# Generated by FakeRAM 2.0
VERSION 5.7 ;
BUSBITCHARS "[]" ;
PROPERTYDEFINITIONS
  MACRO width INTEGER ;
  MACRO depth INTEGER ;
  MACRO banks INTEGER ;
END PROPERTYDEFINITIONS
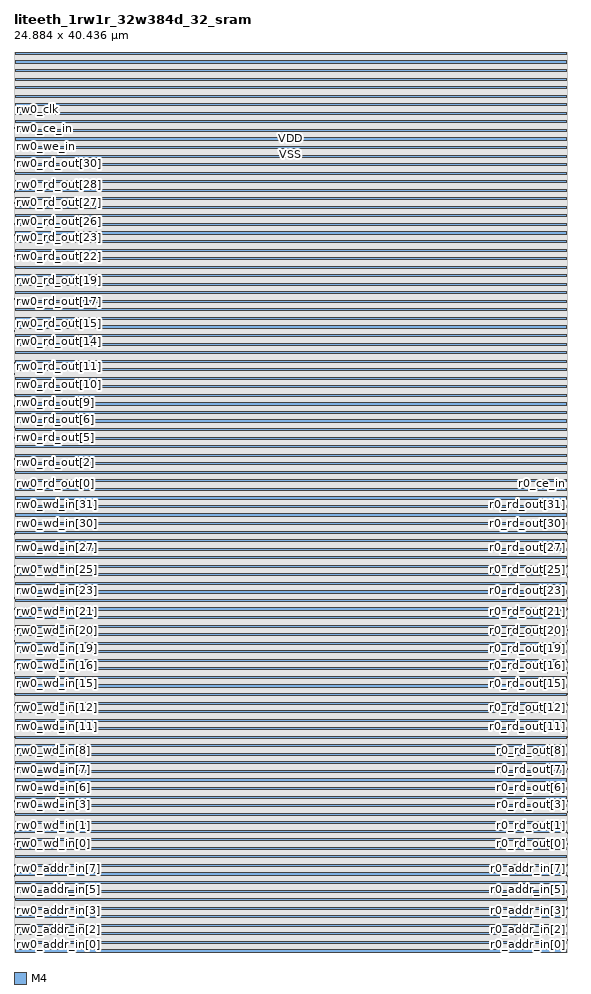
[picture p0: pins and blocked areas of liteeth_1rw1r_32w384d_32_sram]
MACRO liteeth_1rw1r_32w384d_32_sram
  PROPERTY width 32 ;
  PROPERTY depth 384 ;
  PROPERTY banks 1 ;
  FOREIGN liteeth_1rw1r_32w384d_32_sram 0 0 ;
  SYMMETRY X Y R90 ;
  SIZE 24.884 BY 40.436 ;
  CLASS BLOCK ;
  PIN r0_addr_in[0]
    DIRECTION INPUT ;
    USE SIGNAL ;
    SHAPE ABUTMENT ;
    PORT
      LAYER M4 ;
      RECT 24.860 0.048 24.884 0.072 ;
    END
  END r0_addr_in[0]
  PIN r0_addr_in[1]
    DIRECTION INPUT ;
    USE SIGNAL ;
    SHAPE ABUTMENT ;
    PORT
      LAYER M4 ;
      RECT 24.860 0.528 24.884 0.552 ;
    END
  END r0_addr_in[1]
  PIN r0_addr_in[2]
    DIRECTION INPUT ;
    USE SIGNAL ;
    SHAPE ABUTMENT ;
    PORT
      LAYER M4 ;
      RECT 24.860 1.008 24.884 1.032 ;
    END
  END r0_addr_in[2]
  PIN r0_addr_in[3]
    DIRECTION INPUT ;
    USE SIGNAL ;
    SHAPE ABUTMENT ;
    PORT
      LAYER M4 ;
      RECT 24.860 1.488 24.884 1.512 ;
    END
  END r0_addr_in[3]
  PIN r0_addr_in[4]
    DIRECTION INPUT ;
    USE SIGNAL ;
    SHAPE ABUTMENT ;
    PORT
      LAYER M4 ;
      RECT 24.860 1.968 24.884 1.992 ;
    END
  END r0_addr_in[4]
  PIN r0_addr_in[5]
    DIRECTION INPUT ;
    USE SIGNAL ;
    SHAPE ABUTMENT ;
    PORT
      LAYER M4 ;
      RECT 24.860 2.448 24.884 2.472 ;
    END
  END r0_addr_in[5]
  PIN r0_addr_in[6]
    DIRECTION INPUT ;
    USE SIGNAL ;
    SHAPE ABUTMENT ;
    PORT
      LAYER M4 ;
      RECT 24.860 2.928 24.884 2.952 ;
    END
  END r0_addr_in[6]
  PIN r0_addr_in[7]
    DIRECTION INPUT ;
    USE SIGNAL ;
    SHAPE ABUTMENT ;
    PORT
      LAYER M4 ;
      RECT 24.860 3.408 24.884 3.432 ;
    END
  END r0_addr_in[7]
  PIN r0_addr_in[8]
    DIRECTION INPUT ;
    USE SIGNAL ;
    SHAPE ABUTMENT ;
    PORT
      LAYER M4 ;
      RECT 24.860 3.888 24.884 3.912 ;
    END
  END r0_addr_in[8]
  PIN r0_rd_out[0]
    DIRECTION OUTPUT ;
    USE SIGNAL ;
    SHAPE ABUTMENT ;
    PORT
      LAYER M4 ;
      RECT 24.860 4.848 24.884 4.872 ;
    END
  END r0_rd_out[0]
  PIN r0_rd_out[1]
    DIRECTION OUTPUT ;
    USE SIGNAL ;
    SHAPE ABUTMENT ;
    PORT
      LAYER M4 ;
      RECT 24.860 5.328 24.884 5.352 ;
    END
  END r0_rd_out[1]
  PIN r0_rd_out[2]
    DIRECTION OUTPUT ;
    USE SIGNAL ;
    SHAPE ABUTMENT ;
    PORT
      LAYER M4 ;
      RECT 24.860 5.808 24.884 5.832 ;
    END
  END r0_rd_out[2]
  PIN r0_rd_out[3]
    DIRECTION OUTPUT ;
    USE SIGNAL ;
    SHAPE ABUTMENT ;
    PORT
      LAYER M4 ;
      RECT 24.860 6.288 24.884 6.312 ;
    END
  END r0_rd_out[3]
  PIN r0_rd_out[4]
    DIRECTION OUTPUT ;
    USE SIGNAL ;
    SHAPE ABUTMENT ;
    PORT
      LAYER M4 ;
      RECT 24.860 6.768 24.884 6.792 ;
    END
  END r0_rd_out[4]
  PIN r0_rd_out[5]
    DIRECTION OUTPUT ;
    USE SIGNAL ;
    SHAPE ABUTMENT ;
    PORT
      LAYER M4 ;
      RECT 24.860 7.248 24.884 7.272 ;
    END
  END r0_rd_out[5]
  PIN r0_rd_out[6]
    DIRECTION OUTPUT ;
    USE SIGNAL ;
    SHAPE ABUTMENT ;
    PORT
      LAYER M4 ;
      RECT 24.860 7.728 24.884 7.752 ;
    END
  END r0_rd_out[6]
  PIN r0_rd_out[7]
    DIRECTION OUTPUT ;
    USE SIGNAL ;
    SHAPE ABUTMENT ;
    PORT
      LAYER M4 ;
      RECT 24.860 8.208 24.884 8.232 ;
    END
  END r0_rd_out[7]
  PIN r0_rd_out[8]
    DIRECTION OUTPUT ;
    USE SIGNAL ;
    SHAPE ABUTMENT ;
    PORT
      LAYER M4 ;
      RECT 24.860 8.688 24.884 8.712 ;
    END
  END r0_rd_out[8]
  PIN r0_rd_out[9]
    DIRECTION OUTPUT ;
    USE SIGNAL ;
    SHAPE ABUTMENT ;
    PORT
      LAYER M4 ;
      RECT 24.860 9.168 24.884 9.192 ;
    END
  END r0_rd_out[9]
  PIN r0_rd_out[10]
    DIRECTION OUTPUT ;
    USE SIGNAL ;
    SHAPE ABUTMENT ;
    PORT
      LAYER M4 ;
      RECT 24.860 9.648 24.884 9.672 ;
    END
  END r0_rd_out[10]
  PIN r0_rd_out[11]
    DIRECTION OUTPUT ;
    USE SIGNAL ;
    SHAPE ABUTMENT ;
    PORT
      LAYER M4 ;
      RECT 24.860 10.128 24.884 10.152 ;
    END
  END r0_rd_out[11]
  PIN r0_rd_out[12]
    DIRECTION OUTPUT ;
    USE SIGNAL ;
    SHAPE ABUTMENT ;
    PORT
      LAYER M4 ;
      RECT 24.860 10.608 24.884 10.632 ;
    END
  END r0_rd_out[12]
  PIN r0_rd_out[13]
    DIRECTION OUTPUT ;
    USE SIGNAL ;
    SHAPE ABUTMENT ;
    PORT
      LAYER M4 ;
      RECT 24.860 11.088 24.884 11.112 ;
    END
  END r0_rd_out[13]
  PIN r0_rd_out[14]
    DIRECTION OUTPUT ;
    USE SIGNAL ;
    SHAPE ABUTMENT ;
    PORT
      LAYER M4 ;
      RECT 24.860 11.568 24.884 11.592 ;
    END
  END r0_rd_out[14]
  PIN r0_rd_out[15]
    DIRECTION OUTPUT ;
    USE SIGNAL ;
    SHAPE ABUTMENT ;
    PORT
      LAYER M4 ;
      RECT 24.860 12.048 24.884 12.072 ;
    END
  END r0_rd_out[15]
  PIN r0_rd_out[16]
    DIRECTION OUTPUT ;
    USE SIGNAL ;
    SHAPE ABUTMENT ;
    PORT
      LAYER M4 ;
      RECT 24.860 12.528 24.884 12.552 ;
    END
  END r0_rd_out[16]
  PIN r0_rd_out[17]
    DIRECTION OUTPUT ;
    USE SIGNAL ;
    SHAPE ABUTMENT ;
    PORT
      LAYER M4 ;
      RECT 24.860 13.008 24.884 13.032 ;
    END
  END r0_rd_out[17]
  PIN r0_rd_out[18]
    DIRECTION OUTPUT ;
    USE SIGNAL ;
    SHAPE ABUTMENT ;
    PORT
      LAYER M4 ;
      RECT 24.860 13.488 24.884 13.512 ;
    END
  END r0_rd_out[18]
  PIN r0_rd_out[19]
    DIRECTION OUTPUT ;
    USE SIGNAL ;
    SHAPE ABUTMENT ;
    PORT
      LAYER M4 ;
      RECT 24.860 13.968 24.884 13.992 ;
    END
  END r0_rd_out[19]
  PIN r0_rd_out[20]
    DIRECTION OUTPUT ;
    USE SIGNAL ;
    SHAPE ABUTMENT ;
    PORT
      LAYER M4 ;
      RECT 24.860 14.448 24.884 14.472 ;
    END
  END r0_rd_out[20]
  PIN r0_rd_out[21]
    DIRECTION OUTPUT ;
    USE SIGNAL ;
    SHAPE ABUTMENT ;
    PORT
      LAYER M4 ;
      RECT 24.860 14.928 24.884 14.952 ;
    END
  END r0_rd_out[21]
  PIN r0_rd_out[22]
    DIRECTION OUTPUT ;
    USE SIGNAL ;
    SHAPE ABUTMENT ;
    PORT
      LAYER M4 ;
      RECT 24.860 15.408 24.884 15.432 ;
    END
  END r0_rd_out[22]
  PIN r0_rd_out[23]
    DIRECTION OUTPUT ;
    USE SIGNAL ;
    SHAPE ABUTMENT ;
    PORT
      LAYER M4 ;
      RECT 24.860 15.888 24.884 15.912 ;
    END
  END r0_rd_out[23]
  PIN r0_rd_out[24]
    DIRECTION OUTPUT ;
    USE SIGNAL ;
    SHAPE ABUTMENT ;
    PORT
      LAYER M4 ;
      RECT 24.860 16.368 24.884 16.392 ;
    END
  END r0_rd_out[24]
  PIN r0_rd_out[25]
    DIRECTION OUTPUT ;
    USE SIGNAL ;
    SHAPE ABUTMENT ;
    PORT
      LAYER M4 ;
      RECT 24.860 16.848 24.884 16.872 ;
    END
  END r0_rd_out[25]
  PIN r0_rd_out[26]
    DIRECTION OUTPUT ;
    USE SIGNAL ;
    SHAPE ABUTMENT ;
    PORT
      LAYER M4 ;
      RECT 24.860 17.328 24.884 17.352 ;
    END
  END r0_rd_out[26]
  PIN r0_rd_out[27]
    DIRECTION OUTPUT ;
    USE SIGNAL ;
    SHAPE ABUTMENT ;
    PORT
      LAYER M4 ;
      RECT 24.860 17.808 24.884 17.832 ;
    END
  END r0_rd_out[27]
  PIN r0_rd_out[28]
    DIRECTION OUTPUT ;
    USE SIGNAL ;
    SHAPE ABUTMENT ;
    PORT
      LAYER M4 ;
      RECT 24.860 18.288 24.884 18.312 ;
    END
  END r0_rd_out[28]
  PIN r0_rd_out[29]
    DIRECTION OUTPUT ;
    USE SIGNAL ;
    SHAPE ABUTMENT ;
    PORT
      LAYER M4 ;
      RECT 24.860 18.768 24.884 18.792 ;
    END
  END r0_rd_out[29]
  PIN r0_rd_out[30]
    DIRECTION OUTPUT ;
    USE SIGNAL ;
    SHAPE ABUTMENT ;
    PORT
      LAYER M4 ;
      RECT 24.860 19.248 24.884 19.272 ;
    END
  END r0_rd_out[30]
  PIN r0_rd_out[31]
    DIRECTION OUTPUT ;
    USE SIGNAL ;
    SHAPE ABUTMENT ;
    PORT
      LAYER M4 ;
      RECT 24.860 19.728 24.884 19.752 ;
    END
  END r0_rd_out[31]
  PIN r0_ce_in
    DIRECTION INPUT ;
    USE SIGNAL ;
    SHAPE ABUTMENT ;
    PORT
      LAYER M4 ;
      RECT 24.860 20.688 24.884 20.712 ;
    END
  END r0_ce_in
  PIN r0_clk
    DIRECTION INPUT ;
    USE SIGNAL ;
    SHAPE ABUTMENT ;
    PORT
      LAYER M4 ;
      RECT 24.860 21.168 24.884 21.192 ;
    END
  END r0_clk
  PIN rw0_addr_in[0]
    DIRECTION INPUT ;
    USE SIGNAL ;
    SHAPE ABUTMENT ;
    PORT
      LAYER M4 ;
      RECT 0.000 0.048 0.024 0.072 ;
    END
  END rw0_addr_in[0]
  PIN rw0_addr_in[1]
    DIRECTION INPUT ;
    USE SIGNAL ;
    SHAPE ABUTMENT ;
    PORT
      LAYER M4 ;
      RECT 0.000 0.528 0.024 0.552 ;
    END
  END rw0_addr_in[1]
  PIN rw0_addr_in[2]
    DIRECTION INPUT ;
    USE SIGNAL ;
    SHAPE ABUTMENT ;
    PORT
      LAYER M4 ;
      RECT 0.000 1.008 0.024 1.032 ;
    END
  END rw0_addr_in[2]
  PIN rw0_addr_in[3]
    DIRECTION INPUT ;
    USE SIGNAL ;
    SHAPE ABUTMENT ;
    PORT
      LAYER M4 ;
      RECT 0.000 1.488 0.024 1.512 ;
    END
  END rw0_addr_in[3]
  PIN rw0_addr_in[4]
    DIRECTION INPUT ;
    USE SIGNAL ;
    SHAPE ABUTMENT ;
    PORT
      LAYER M4 ;
      RECT 0.000 1.968 0.024 1.992 ;
    END
  END rw0_addr_in[4]
  PIN rw0_addr_in[5]
    DIRECTION INPUT ;
    USE SIGNAL ;
    SHAPE ABUTMENT ;
    PORT
      LAYER M4 ;
      RECT 0.000 2.448 0.024 2.472 ;
    END
  END rw0_addr_in[5]
  PIN rw0_addr_in[6]
    DIRECTION INPUT ;
    USE SIGNAL ;
    SHAPE ABUTMENT ;
    PORT
      LAYER M4 ;
      RECT 0.000 2.928 0.024 2.952 ;
    END
  END rw0_addr_in[6]
  PIN rw0_addr_in[7]
    DIRECTION INPUT ;
    USE SIGNAL ;
    SHAPE ABUTMENT ;
    PORT
      LAYER M4 ;
      RECT 0.000 3.408 0.024 3.432 ;
    END
  END rw0_addr_in[7]
  PIN rw0_addr_in[8]
    DIRECTION INPUT ;
    USE SIGNAL ;
    SHAPE ABUTMENT ;
    PORT
      LAYER M4 ;
      RECT 0.000 3.888 0.024 3.912 ;
    END
  END rw0_addr_in[8]
  PIN rw0_wd_in[0]
    DIRECTION INPUT ;
    USE SIGNAL ;
    SHAPE ABUTMENT ;
    PORT
      LAYER M4 ;
      RECT 0.000 4.848 0.024 4.872 ;
    END
  END rw0_wd_in[0]
  PIN rw0_wd_in[1]
    DIRECTION INPUT ;
    USE SIGNAL ;
    SHAPE ABUTMENT ;
    PORT
      LAYER M4 ;
      RECT 0.000 5.328 0.024 5.352 ;
    END
  END rw0_wd_in[1]
  PIN rw0_wd_in[2]
    DIRECTION INPUT ;
    USE SIGNAL ;
    SHAPE ABUTMENT ;
    PORT
      LAYER M4 ;
      RECT 0.000 5.808 0.024 5.832 ;
    END
  END rw0_wd_in[2]
  PIN rw0_wd_in[3]
    DIRECTION INPUT ;
    USE SIGNAL ;
    SHAPE ABUTMENT ;
    PORT
      LAYER M4 ;
      RECT 0.000 6.288 0.024 6.312 ;
    END
  END rw0_wd_in[3]
  PIN rw0_wd_in[4]
    DIRECTION INPUT ;
    USE SIGNAL ;
    SHAPE ABUTMENT ;
    PORT
      LAYER M4 ;
      RECT 0.000 6.768 0.024 6.792 ;
    END
  END rw0_wd_in[4]
  PIN rw0_wd_in[5]
    DIRECTION INPUT ;
    USE SIGNAL ;
    SHAPE ABUTMENT ;
    PORT
      LAYER M4 ;
      RECT 0.000 7.248 0.024 7.272 ;
    END
  END rw0_wd_in[5]
  PIN rw0_wd_in[6]
    DIRECTION INPUT ;
    USE SIGNAL ;
    SHAPE ABUTMENT ;
    PORT
      LAYER M4 ;
      RECT 0.000 7.728 0.024 7.752 ;
    END
  END rw0_wd_in[6]
  PIN rw0_wd_in[7]
    DIRECTION INPUT ;
    USE SIGNAL ;
    SHAPE ABUTMENT ;
    PORT
      LAYER M4 ;
      RECT 0.000 8.208 0.024 8.232 ;
    END
  END rw0_wd_in[7]
  PIN rw0_wd_in[8]
    DIRECTION INPUT ;
    USE SIGNAL ;
    SHAPE ABUTMENT ;
    PORT
      LAYER M4 ;
      RECT 0.000 8.688 0.024 8.712 ;
    END
  END rw0_wd_in[8]
  PIN rw0_wd_in[9]
    DIRECTION INPUT ;
    USE SIGNAL ;
    SHAPE ABUTMENT ;
    PORT
      LAYER M4 ;
      RECT 0.000 9.168 0.024 9.192 ;
    END
  END rw0_wd_in[9]
  PIN rw0_wd_in[10]
    DIRECTION INPUT ;
    USE SIGNAL ;
    SHAPE ABUTMENT ;
    PORT
      LAYER M4 ;
      RECT 0.000 9.648 0.024 9.672 ;
    END
  END rw0_wd_in[10]
  PIN rw0_wd_in[11]
    DIRECTION INPUT ;
    USE SIGNAL ;
    SHAPE ABUTMENT ;
    PORT
      LAYER M4 ;
      RECT 0.000 10.128 0.024 10.152 ;
    END
  END rw0_wd_in[11]
  PIN rw0_wd_in[12]
    DIRECTION INPUT ;
    USE SIGNAL ;
    SHAPE ABUTMENT ;
    PORT
      LAYER M4 ;
      RECT 0.000 10.608 0.024 10.632 ;
    END
  END rw0_wd_in[12]
  PIN rw0_wd_in[13]
    DIRECTION INPUT ;
    USE SIGNAL ;
    SHAPE ABUTMENT ;
    PORT
      LAYER M4 ;
      RECT 0.000 11.088 0.024 11.112 ;
    END
  END rw0_wd_in[13]
  PIN rw0_wd_in[14]
    DIRECTION INPUT ;
    USE SIGNAL ;
    SHAPE ABUTMENT ;
    PORT
      LAYER M4 ;
      RECT 0.000 11.568 0.024 11.592 ;
    END
  END rw0_wd_in[14]
  PIN rw0_wd_in[15]
    DIRECTION INPUT ;
    USE SIGNAL ;
    SHAPE ABUTMENT ;
    PORT
      LAYER M4 ;
      RECT 0.000 12.048 0.024 12.072 ;
    END
  END rw0_wd_in[15]
  PIN rw0_wd_in[16]
    DIRECTION INPUT ;
    USE SIGNAL ;
    SHAPE ABUTMENT ;
    PORT
      LAYER M4 ;
      RECT 0.000 12.528 0.024 12.552 ;
    END
  END rw0_wd_in[16]
  PIN rw0_wd_in[17]
    DIRECTION INPUT ;
    USE SIGNAL ;
    SHAPE ABUTMENT ;
    PORT
      LAYER M4 ;
      RECT 0.000 13.008 0.024 13.032 ;
    END
  END rw0_wd_in[17]
  PIN rw0_wd_in[18]
    DIRECTION INPUT ;
    USE SIGNAL ;
    SHAPE ABUTMENT ;
    PORT
      LAYER M4 ;
      RECT 0.000 13.488 0.024 13.512 ;
    END
  END rw0_wd_in[18]
  PIN rw0_wd_in[19]
    DIRECTION INPUT ;
    USE SIGNAL ;
    SHAPE ABUTMENT ;
    PORT
      LAYER M4 ;
      RECT 0.000 13.968 0.024 13.992 ;
    END
  END rw0_wd_in[19]
  PIN rw0_wd_in[20]
    DIRECTION INPUT ;
    USE SIGNAL ;
    SHAPE ABUTMENT ;
    PORT
      LAYER M4 ;
      RECT 0.000 14.448 0.024 14.472 ;
    END
  END rw0_wd_in[20]
  PIN rw0_wd_in[21]
    DIRECTION INPUT ;
    USE SIGNAL ;
    SHAPE ABUTMENT ;
    PORT
      LAYER M4 ;
      RECT 0.000 14.928 0.024 14.952 ;
    END
  END rw0_wd_in[21]
  PIN rw0_wd_in[22]
    DIRECTION INPUT ;
    USE SIGNAL ;
    SHAPE ABUTMENT ;
    PORT
      LAYER M4 ;
      RECT 0.000 15.408 0.024 15.432 ;
    END
  END rw0_wd_in[22]
  PIN rw0_wd_in[23]
    DIRECTION INPUT ;
    USE SIGNAL ;
    SHAPE ABUTMENT ;
    PORT
      LAYER M4 ;
      RECT 0.000 15.888 0.024 15.912 ;
    END
  END rw0_wd_in[23]
  PIN rw0_wd_in[24]
    DIRECTION INPUT ;
    USE SIGNAL ;
    SHAPE ABUTMENT ;
    PORT
      LAYER M4 ;
      RECT 0.000 16.368 0.024 16.392 ;
    END
  END rw0_wd_in[24]
  PIN rw0_wd_in[25]
    DIRECTION INPUT ;
    USE SIGNAL ;
    SHAPE ABUTMENT ;
    PORT
      LAYER M4 ;
      RECT 0.000 16.848 0.024 16.872 ;
    END
  END rw0_wd_in[25]
  PIN rw0_wd_in[26]
    DIRECTION INPUT ;
    USE SIGNAL ;
    SHAPE ABUTMENT ;
    PORT
      LAYER M4 ;
      RECT 0.000 17.328 0.024 17.352 ;
    END
  END rw0_wd_in[26]
  PIN rw0_wd_in[27]
    DIRECTION INPUT ;
    USE SIGNAL ;
    SHAPE ABUTMENT ;
    PORT
      LAYER M4 ;
      RECT 0.000 17.808 0.024 17.832 ;
    END
  END rw0_wd_in[27]
  PIN rw0_wd_in[28]
    DIRECTION INPUT ;
    USE SIGNAL ;
    SHAPE ABUTMENT ;
    PORT
      LAYER M4 ;
      RECT 0.000 18.288 0.024 18.312 ;
    END
  END rw0_wd_in[28]
  PIN rw0_wd_in[29]
    DIRECTION INPUT ;
    USE SIGNAL ;
    SHAPE ABUTMENT ;
    PORT
      LAYER M4 ;
      RECT 0.000 18.768 0.024 18.792 ;
    END
  END rw0_wd_in[29]
  PIN rw0_wd_in[30]
    DIRECTION INPUT ;
    USE SIGNAL ;
    SHAPE ABUTMENT ;
    PORT
      LAYER M4 ;
      RECT 0.000 19.248 0.024 19.272 ;
    END
  END rw0_wd_in[30]
  PIN rw0_wd_in[31]
    DIRECTION INPUT ;
    USE SIGNAL ;
    SHAPE ABUTMENT ;
    PORT
      LAYER M4 ;
      RECT 0.000 19.728 0.024 19.752 ;
    END
  END rw0_wd_in[31]
  PIN rw0_rd_out[0]
    DIRECTION OUTPUT ;
    USE SIGNAL ;
    SHAPE ABUTMENT ;
    PORT
      LAYER M4 ;
      RECT 0.000 20.688 0.024 20.712 ;
    END
  END rw0_rd_out[0]
  PIN rw0_rd_out[1]
    DIRECTION OUTPUT ;
    USE SIGNAL ;
    SHAPE ABUTMENT ;
    PORT
      LAYER M4 ;
      RECT 0.000 21.168 0.024 21.192 ;
    END
  END rw0_rd_out[1]
  PIN rw0_rd_out[2]
    DIRECTION OUTPUT ;
    USE SIGNAL ;
    SHAPE ABUTMENT ;
    PORT
      LAYER M4 ;
      RECT 0.000 21.648 0.024 21.672 ;
    END
  END rw0_rd_out[2]
  PIN rw0_rd_out[3]
    DIRECTION OUTPUT ;
    USE SIGNAL ;
    SHAPE ABUTMENT ;
    PORT
      LAYER M4 ;
      RECT 0.000 22.128 0.024 22.152 ;
    END
  END rw0_rd_out[3]
  PIN rw0_rd_out[4]
    DIRECTION OUTPUT ;
    USE SIGNAL ;
    SHAPE ABUTMENT ;
    PORT
      LAYER M4 ;
      RECT 0.000 22.608 0.024 22.632 ;
    END
  END rw0_rd_out[4]
  PIN rw0_rd_out[5]
    DIRECTION OUTPUT ;
    USE SIGNAL ;
    SHAPE ABUTMENT ;
    PORT
      LAYER M4 ;
      RECT 0.000 23.088 0.024 23.112 ;
    END
  END rw0_rd_out[5]
  PIN rw0_rd_out[6]
    DIRECTION OUTPUT ;
    USE SIGNAL ;
    SHAPE ABUTMENT ;
    PORT
      LAYER M4 ;
      RECT 0.000 23.568 0.024 23.592 ;
    END
  END rw0_rd_out[6]
  PIN rw0_rd_out[7]
    DIRECTION OUTPUT ;
    USE SIGNAL ;
    SHAPE ABUTMENT ;
    PORT
      LAYER M4 ;
      RECT 0.000 24.048 0.024 24.072 ;
    END
  END rw0_rd_out[7]
  PIN rw0_rd_out[8]
    DIRECTION OUTPUT ;
    USE SIGNAL ;
    SHAPE ABUTMENT ;
    PORT
      LAYER M4 ;
      RECT 0.000 24.528 0.024 24.552 ;
    END
  END rw0_rd_out[8]
  PIN rw0_rd_out[9]
    DIRECTION OUTPUT ;
    USE SIGNAL ;
    SHAPE ABUTMENT ;
    PORT
      LAYER M4 ;
      RECT 0.000 25.008 0.024 25.032 ;
    END
  END rw0_rd_out[9]
  PIN rw0_rd_out[10]
    DIRECTION OUTPUT ;
    USE SIGNAL ;
    SHAPE ABUTMENT ;
    PORT
      LAYER M4 ;
      RECT 0.000 25.488 0.024 25.512 ;
    END
  END rw0_rd_out[10]
  PIN rw0_rd_out[11]
    DIRECTION OUTPUT ;
    USE SIGNAL ;
    SHAPE ABUTMENT ;
    PORT
      LAYER M4 ;
      RECT 0.000 25.968 0.024 25.992 ;
    END
  END rw0_rd_out[11]
  PIN rw0_rd_out[12]
    DIRECTION OUTPUT ;
    USE SIGNAL ;
    SHAPE ABUTMENT ;
    PORT
      LAYER M4 ;
      RECT 0.000 26.448 0.024 26.472 ;
    END
  END rw0_rd_out[12]
  PIN rw0_rd_out[13]
    DIRECTION OUTPUT ;
    USE SIGNAL ;
    SHAPE ABUTMENT ;
    PORT
      LAYER M4 ;
      RECT 0.000 26.928 0.024 26.952 ;
    END
  END rw0_rd_out[13]
  PIN rw0_rd_out[14]
    DIRECTION OUTPUT ;
    USE SIGNAL ;
    SHAPE ABUTMENT ;
    PORT
      LAYER M4 ;
      RECT 0.000 27.408 0.024 27.432 ;
    END
  END rw0_rd_out[14]
  PIN rw0_rd_out[15]
    DIRECTION OUTPUT ;
    USE SIGNAL ;
    SHAPE ABUTMENT ;
    PORT
      LAYER M4 ;
      RECT 0.000 27.888 0.024 27.912 ;
    END
  END rw0_rd_out[15]
  PIN rw0_rd_out[16]
    DIRECTION OUTPUT ;
    USE SIGNAL ;
    SHAPE ABUTMENT ;
    PORT
      LAYER M4 ;
      RECT 0.000 28.368 0.024 28.392 ;
    END
  END rw0_rd_out[16]
  PIN rw0_rd_out[17]
    DIRECTION OUTPUT ;
    USE SIGNAL ;
    SHAPE ABUTMENT ;
    PORT
      LAYER M4 ;
      RECT 0.000 28.848 0.024 28.872 ;
    END
  END rw0_rd_out[17]
  PIN rw0_rd_out[18]
    DIRECTION OUTPUT ;
    USE SIGNAL ;
    SHAPE ABUTMENT ;
    PORT
      LAYER M4 ;
      RECT 0.000 29.328 0.024 29.352 ;
    END
  END rw0_rd_out[18]
  PIN rw0_rd_out[19]
    DIRECTION OUTPUT ;
    USE SIGNAL ;
    SHAPE ABUTMENT ;
    PORT
      LAYER M4 ;
      RECT 0.000 29.808 0.024 29.832 ;
    END
  END rw0_rd_out[19]
  PIN rw0_rd_out[20]
    DIRECTION OUTPUT ;
    USE SIGNAL ;
    SHAPE ABUTMENT ;
    PORT
      LAYER M4 ;
      RECT 0.000 30.288 0.024 30.312 ;
    END
  END rw0_rd_out[20]
  PIN rw0_rd_out[21]
    DIRECTION OUTPUT ;
    USE SIGNAL ;
    SHAPE ABUTMENT ;
    PORT
      LAYER M4 ;
      RECT 0.000 30.768 0.024 30.792 ;
    END
  END rw0_rd_out[21]
  PIN rw0_rd_out[22]
    DIRECTION OUTPUT ;
    USE SIGNAL ;
    SHAPE ABUTMENT ;
    PORT
      LAYER M4 ;
      RECT 0.000 31.248 0.024 31.272 ;
    END
  END rw0_rd_out[22]
  PIN rw0_rd_out[23]
    DIRECTION OUTPUT ;
    USE SIGNAL ;
    SHAPE ABUTMENT ;
    PORT
      LAYER M4 ;
      RECT 0.000 31.728 0.024 31.752 ;
    END
  END rw0_rd_out[23]
  PIN rw0_rd_out[24]
    DIRECTION OUTPUT ;
    USE SIGNAL ;
    SHAPE ABUTMENT ;
    PORT
      LAYER M4 ;
      RECT 0.000 32.208 0.024 32.232 ;
    END
  END rw0_rd_out[24]
  PIN rw0_rd_out[25]
    DIRECTION OUTPUT ;
    USE SIGNAL ;
    SHAPE ABUTMENT ;
    PORT
      LAYER M4 ;
      RECT 0.000 32.688 0.024 32.712 ;
    END
  END rw0_rd_out[25]
  PIN rw0_rd_out[26]
    DIRECTION OUTPUT ;
    USE SIGNAL ;
    SHAPE ABUTMENT ;
    PORT
      LAYER M4 ;
      RECT 0.000 33.168 0.024 33.192 ;
    END
  END rw0_rd_out[26]
  PIN rw0_rd_out[27]
    DIRECTION OUTPUT ;
    USE SIGNAL ;
    SHAPE ABUTMENT ;
    PORT
      LAYER M4 ;
      RECT 0.000 33.648 0.024 33.672 ;
    END
  END rw0_rd_out[27]
  PIN rw0_rd_out[28]
    DIRECTION OUTPUT ;
    USE SIGNAL ;
    SHAPE ABUTMENT ;
    PORT
      LAYER M4 ;
      RECT 0.000 34.128 0.024 34.152 ;
    END
  END rw0_rd_out[28]
  PIN rw0_rd_out[29]
    DIRECTION OUTPUT ;
    USE SIGNAL ;
    SHAPE ABUTMENT ;
    PORT
      LAYER M4 ;
      RECT 0.000 34.608 0.024 34.632 ;
    END
  END rw0_rd_out[29]
  PIN rw0_rd_out[30]
    DIRECTION OUTPUT ;
    USE SIGNAL ;
    SHAPE ABUTMENT ;
    PORT
      LAYER M4 ;
      RECT 0.000 35.088 0.024 35.112 ;
    END
  END rw0_rd_out[30]
  PIN rw0_rd_out[31]
    DIRECTION OUTPUT ;
    USE SIGNAL ;
    SHAPE ABUTMENT ;
    PORT
      LAYER M4 ;
      RECT 0.000 35.568 0.024 35.592 ;
    END
  END rw0_rd_out[31]
  PIN rw0_we_in
    DIRECTION INPUT ;
    USE SIGNAL ;
    SHAPE ABUTMENT ;
    PORT
      LAYER M4 ;
      RECT 0.000 36.528 0.024 36.552 ;
    END
  END rw0_we_in
  PIN rw0_ce_in
    DIRECTION INPUT ;
    USE SIGNAL ;
    SHAPE ABUTMENT ;
    PORT
      LAYER M4 ;
      RECT 0.000 37.008 0.024 37.032 ;
    END
  END rw0_ce_in
  PIN rw0_clk
    DIRECTION INPUT ;
    USE SIGNAL ;
    SHAPE ABUTMENT ;
    PORT
      LAYER M4 ;
      RECT 0.000 37.488 0.024 37.512 ;
    END
  END rw0_clk
  PIN VSS
    DIRECTION INOUT ;
    USE GROUND ;
    PORT
      LAYER M4 ;
      RECT 0.048 0.000 24.836 0.096 ;
      RECT 0.048 0.768 24.836 0.864 ;
      RECT 0.048 1.536 24.836 1.632 ;
      RECT 0.048 2.304 24.836 2.400 ;
      RECT 0.048 3.072 24.836 3.168 ;
      RECT 0.048 3.840 24.836 3.936 ;
      RECT 0.048 4.608 24.836 4.704 ;
      RECT 0.048 5.376 24.836 5.472 ;
      RECT 0.048 6.144 24.836 6.240 ;
      RECT 0.048 6.912 24.836 7.008 ;
      RECT 0.048 7.680 24.836 7.776 ;
      RECT 0.048 8.448 24.836 8.544 ;
      RECT 0.048 9.216 24.836 9.312 ;
      RECT 0.048 9.984 24.836 10.080 ;
      RECT 0.048 10.752 24.836 10.848 ;
      RECT 0.048 11.520 24.836 11.616 ;
      RECT 0.048 12.288 24.836 12.384 ;
      RECT 0.048 13.056 24.836 13.152 ;
      RECT 0.048 13.824 24.836 13.920 ;
      RECT 0.048 14.592 24.836 14.688 ;
      RECT 0.048 15.360 24.836 15.456 ;
      RECT 0.048 16.128 24.836 16.224 ;
      RECT 0.048 16.896 24.836 16.992 ;
      RECT 0.048 17.664 24.836 17.760 ;
      RECT 0.048 18.432 24.836 18.528 ;
      RECT 0.048 19.200 24.836 19.296 ;
      RECT 0.048 19.968 24.836 20.064 ;
      RECT 0.048 20.736 24.836 20.832 ;
      RECT 0.048 21.504 24.836 21.600 ;
      RECT 0.048 22.272 24.836 22.368 ;
      RECT 0.048 23.040 24.836 23.136 ;
      RECT 0.048 23.808 24.836 23.904 ;
      RECT 0.048 24.576 24.836 24.672 ;
      RECT 0.048 25.344 24.836 25.440 ;
      RECT 0.048 26.112 24.836 26.208 ;
      RECT 0.048 26.880 24.836 26.976 ;
      RECT 0.048 27.648 24.836 27.744 ;
      RECT 0.048 28.416 24.836 28.512 ;
      RECT 0.048 29.184 24.836 29.280 ;
      RECT 0.048 29.952 24.836 30.048 ;
      RECT 0.048 30.720 24.836 30.816 ;
      RECT 0.048 31.488 24.836 31.584 ;
      RECT 0.048 32.256 24.836 32.352 ;
      RECT 0.048 33.024 24.836 33.120 ;
      RECT 0.048 33.792 24.836 33.888 ;
      RECT 0.048 34.560 24.836 34.656 ;
      RECT 0.048 35.328 24.836 35.424 ;
      RECT 0.048 36.096 24.836 36.192 ;
      RECT 0.048 36.864 24.836 36.960 ;
      RECT 0.048 37.632 24.836 37.728 ;
      RECT 0.048 38.400 24.836 38.496 ;
      RECT 0.048 39.168 24.836 39.264 ;
      RECT 0.048 39.936 24.836 40.032 ;
    END
  END VSS
  PIN VDD
    DIRECTION INOUT ;
    USE POWER ;
    PORT
      LAYER M4 ;
      RECT 0.048 0.384 24.836 0.480 ;
      RECT 0.048 1.152 24.836 1.248 ;
      RECT 0.048 1.920 24.836 2.016 ;
      RECT 0.048 2.688 24.836 2.784 ;
      RECT 0.048 3.456 24.836 3.552 ;
      RECT 0.048 4.224 24.836 4.320 ;
      RECT 0.048 4.992 24.836 5.088 ;
      RECT 0.048 5.760 24.836 5.856 ;
      RECT 0.048 6.528 24.836 6.624 ;
      RECT 0.048 7.296 24.836 7.392 ;
      RECT 0.048 8.064 24.836 8.160 ;
      RECT 0.048 8.832 24.836 8.928 ;
      RECT 0.048 9.600 24.836 9.696 ;
      RECT 0.048 10.368 24.836 10.464 ;
      RECT 0.048 11.136 24.836 11.232 ;
      RECT 0.048 11.904 24.836 12.000 ;
      RECT 0.048 12.672 24.836 12.768 ;
      RECT 0.048 13.440 24.836 13.536 ;
      RECT 0.048 14.208 24.836 14.304 ;
      RECT 0.048 14.976 24.836 15.072 ;
      RECT 0.048 15.744 24.836 15.840 ;
      RECT 0.048 16.512 24.836 16.608 ;
      RECT 0.048 17.280 24.836 17.376 ;
      RECT 0.048 18.048 24.836 18.144 ;
      RECT 0.048 18.816 24.836 18.912 ;
      RECT 0.048 19.584 24.836 19.680 ;
      RECT 0.048 20.352 24.836 20.448 ;
      RECT 0.048 21.120 24.836 21.216 ;
      RECT 0.048 21.888 24.836 21.984 ;
      RECT 0.048 22.656 24.836 22.752 ;
      RECT 0.048 23.424 24.836 23.520 ;
      RECT 0.048 24.192 24.836 24.288 ;
      RECT 0.048 24.960 24.836 25.056 ;
      RECT 0.048 25.728 24.836 25.824 ;
      RECT 0.048 26.496 24.836 26.592 ;
      RECT 0.048 27.264 24.836 27.360 ;
      RECT 0.048 28.032 24.836 28.128 ;
      RECT 0.048 28.800 24.836 28.896 ;
      RECT 0.048 29.568 24.836 29.664 ;
      RECT 0.048 30.336 24.836 30.432 ;
      RECT 0.048 31.104 24.836 31.200 ;
      RECT 0.048 31.872 24.836 31.968 ;
      RECT 0.048 32.640 24.836 32.736 ;
      RECT 0.048 33.408 24.836 33.504 ;
      RECT 0.048 34.176 24.836 34.272 ;
      RECT 0.048 34.944 24.836 35.040 ;
      RECT 0.048 35.712 24.836 35.808 ;
      RECT 0.048 36.480 24.836 36.576 ;
      RECT 0.048 37.248 24.836 37.344 ;
      RECT 0.048 38.016 24.836 38.112 ;
      RECT 0.048 38.784 24.836 38.880 ;
      RECT 0.048 39.552 24.836 39.648 ;
      RECT 0.048 40.320 24.836 40.416 ;
    END
  END VDD
  OBS
    LAYER M1 ;
    RECT 0 0 24.884 40.436 ;
    LAYER M2 ;
    RECT 0 0 24.884 40.436 ;
    LAYER M3 ;
    RECT 0 0 24.884 40.436 ;
    LAYER M4 ;
    RECT 0 0 24.884 40.436 ;
  END
END liteeth_1rw1r_32w384d_32_sram

END LIBRARY
